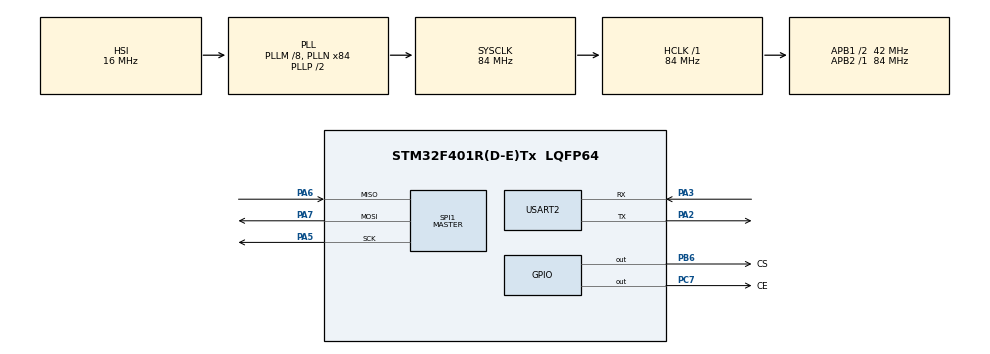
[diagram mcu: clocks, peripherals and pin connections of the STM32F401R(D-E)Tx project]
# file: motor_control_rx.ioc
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Mcu.Family=STM32F4
Mcu.Name=STM32F401R(D-E)Tx
Mcu.Package=LQFP64
NVIC.PriorityGroup=NVIC_PRIORITYGROUP_4
PA2.Mode=Asynchronous
PA2.Signal=USART2_TX
PA3.Mode=Asynchronous
PA3.Signal=USART2_RX
PA5.Mode=Full_Duplex_Master
PA5.Signal=SPI1_SCK
PA6.Mode=Full_Duplex_Master
PA6.Signal=SPI1_MISO
PA7.Mode=Full_Duplex_Master
PA7.Signal=SPI1_MOSI
PB6.GPIO_Label=CS
PB6.PinState=GPIO_PIN_SET
PB6.Signal=GPIO_Output
PC7.GPIO_Label=CE
PC7.Signal=GPIO_Output
ProjectManager.HeapSize=0x200
ProjectManager.StackSize=0x400
ProjectManager.TargetToolchain=STM32CubeIDE
RCC.48MHZClocksFreq_Value=42000000
RCC.AHBFreq_Value=84000000
RCC.APB1CLKDivider=RCC_HCLK_DIV2
RCC.APB1Freq_Value=42000000
RCC.APB1TimFreq_Value=84000000
RCC.APB2Freq_Value=84000000
RCC.APB2TimFreq_Value=84000000
RCC.CortexFreq_Value=84000000
RCC.HCLKFreq_Value=84000000
RCC.HSE_VALUE=25000000
RCC.HSI_VALUE=16000000
RCC.LSE_VALUE=32768
RCC.PLLM=8
RCC.PLLN=84
RCC.SYSCLKFreq_VALUE=84000000
RCC.SYSCLKSource=RCC_SYSCLKSOURCE_PLLCLK
RCC.VCOOutputFreq_Value=168000000
SPI1.BaudRatePrescaler=SPI_BAUDRATEPRESCALER_16
SPI1.Direction=SPI_DIRECTION_2LINES
SPI1.Mode=SPI_MODE_MASTER
SPI1.VirtualType=VM_MASTER
USART2.VirtualMode=VM_ASYNC
board=custom

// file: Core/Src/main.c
/* USER CODE BEGIN Header */
/**
  ******************************************************************************
  * @file           : main.c
  * @brief          : Main program body
  ******************************************************************************
  * @attention
  *
  * This program is setup to receive the joystick X and Y coordinates from the motor
  * control tx project. The coordinates will determine which direction(forward or reverse)
  * to set the motors in.
  *
  * Copyright (c) 2025 STMicroelectronics.
  * All rights reserved.
  *
  * This software is licensed under terms that can be found in the LICENSE file
  * in the root directory of this software component.
  * If no LICENSE file comes with this software, it is provided AS-IS.
  *
  ******************************************************************************
  */
/* USER CODE END Header */
#include "main.h"

/* USER CODE BEGIN Includes */
#include "NRF24L01.h"
#include "string.h"
#include "stdio.h"
/* USER CODE END Includes */

SPI_HandleTypeDef hspi1;

UART_HandleTypeDef huart2;

void SystemClock_Config(void);
static void MX_GPIO_Init(void);
static void MX_SPI1_Init(void);
static void MX_USART2_UART_Init(void);

/* USER CODE BEGIN 0 */

#define JOYSTICK_IN1_PORT GPIOA
#define JOYSTICK_IN1_PIN  GPIO_PIN_9
#define JOYSTICK_IN2_PORT GPIOA
#define JOYSTICK_IN2_PIN  GPIO_PIN_8
#define JOYSTICK_IN3_PORT GPIOB
#define JOYSTICK_IN3_PIN  GPIO_PIN_5
#define JOYSTICK_IN4_PORT GPIOB
#define JOYSTICK_IN4_PIN  GPIO_PIN_3

uint8_t rx_addr[] = {0xEE, 0xDD, 0xCC, 0xBB, 0xAA};
uint8_t rx_data[32];
char coordinate_arr[100];
uint8_t x_coordinate_val = 0;
uint8_t y_coordinate_val = 0;
uint8_t xy_coordinate_val[2];

// This function receives the x and y coordinates from the NRF24L01 rx module
// and assigns it to a  variable. This variable is later used to set the direction
// in the direction function
void joystick_coordiantes_rx()
{
		  if (data_available(1)==1)
		  {
			  rx(rx_data);

			  //rx buffer has the x data on the 0th element and y data on the 4th element due to a
			  //conversion from uint32_t to uint8_t in the motor_control tx project
			  xy_coordinate_val[0] = rx_data[0];
			  xy_coordinate_val[1] = rx_data[4];

			  //Used to debug and verify the correct coordinates are being transmitted to the NRF24L01 Receiver
			  sprintf(coordinate_arr,  "\rX-Coordinate: %d Y-Coordinate: %d \n", xy_coordinate_val[0],xy_coordinate_val[1]);
			  HAL_UART_Transmit(&huart2, (uint8_t*)coordinate_arr, 50, 1000);
		  }
}

//This function will execute a specific direction function for the motors
//based on the updated x and y coordinate values
void direction()
{

	while(1){

		joystick_coordiantes_rx();

		x_coordinate_val = xy_coordinate_val[0];
		y_coordinate_val = xy_coordinate_val[1];

		if (y_coordinate_val < 100)
		{
			forward(y_coordinate_val);
		}
		else if (y_coordinate_val > 160)
		{
			reverse(y_coordinate_val);
		}
		else if (x_coordinate_val >160)
		{
			clockwise(x_coordinate_val);
		}

		else if (x_coordinate_val <100)
		{
			counter_clockwise(x_coordinate_val);
		}

		else
		{
			no_move();
		}
	}

}

//This function sets both motors in the forward direction
void forward(y_coordinate_val)
{
	//check if were still moving in the same direction
	while(y_coordinate_val < 100)
	{
		HAL_GPIO_WritePin (JOYSTICK_IN1_PORT, JOYSTICK_IN1_PIN, 1);
		HAL_GPIO_WritePin (JOYSTICK_IN2_PORT, JOYSTICK_IN2_PIN, 0);
		HAL_GPIO_WritePin (JOYSTICK_IN3_PORT, JOYSTICK_IN3_PIN, 1);
		HAL_GPIO_WritePin (JOYSTICK_IN4_PORT, JOYSTICK_IN4_PIN, 0);

		//assigns xy_coordinate_val array to a new set of x and y coordinates from the RF module
		joystick_coordiantes_rx();

		//update y variable to use the most updated joystick value
		y_coordinate_val = xy_coordinate_val[1];
	}
}

//This function sets both motors in the reverse direction
void reverse(y_coordinate_val)
{
	//check if were still moving in the same direction
	while(y_coordinate_val > 160)
	{
		HAL_GPIO_WritePin (JOYSTICK_IN1_PORT, JOYSTICK_IN1_PIN, 0);
		HAL_GPIO_WritePin (JOYSTICK_IN2_PORT, JOYSTICK_IN2_PIN, 1);
		HAL_GPIO_WritePin (JOYSTICK_IN3_PORT, JOYSTICK_IN3_PIN, 0);
		HAL_GPIO_WritePin (JOYSTICK_IN4_PORT, JOYSTICK_IN4_PIN, 1);

		//assigns xy_coordinate_val array to a new set of x and y coordinates from the RF module
		joystick_coordiantes_rx();

		//update y variable to use the most updated joystick value
		y_coordinate_val = xy_coordinate_val[1];
	}
}

//This function sets the left motor in the forward direction and turns the right motor off
void clockwise(x_coordinate_val)
{
	//check if were still moving in the same direction
	while(x_coordinate_val > 160)
	{
		HAL_GPIO_WritePin (JOYSTICK_IN1_PORT, JOYSTICK_IN1_PIN, 1);
		HAL_GPIO_WritePin (JOYSTICK_IN2_PORT, JOYSTICK_IN2_PIN, 0);
		HAL_GPIO_WritePin (JOYSTICK_IN3_PORT, JOYSTICK_IN3_PIN, 0);
		HAL_GPIO_WritePin (JOYSTICK_IN4_PORT, JOYSTICK_IN4_PIN, 0);

		//assigns xy_coordinate_val array to a new set of x and y coordinates from the RF module
		joystick_coordiantes_rx();

		//update y variable to use the most updated joystick value
		x_coordinate_val = xy_coordinate_val[0];
	}
}

//This function sets the right motor in the forward direction and turns the left motor off
void counter_clockwise(x_coordinate_val)
{
	//check if were still moving in the same direction
	while(x_coordinate_val < 100)
	{
		HAL_GPIO_WritePin (JOYSTICK_IN1_PORT, JOYSTICK_IN1_PIN, 0);
		HAL_GPIO_WritePin (JOYSTICK_IN2_PORT, JOYSTICK_IN2_PIN, 0);
		HAL_GPIO_WritePin (JOYSTICK_IN3_PORT, JOYSTICK_IN3_PIN, 1);
		HAL_GPIO_WritePin (JOYSTICK_IN4_PORT, JOYSTICK_IN4_PIN, 0);

		//assigns xy_coordinate_val array to a new set of x and y coordinates from the RF module
		joystick_coordiantes_rx();

		//update y variable to use the most updated joystick value
		x_coordinate_val = xy_coordinate_val[0];
	}
}

//turn both motors off
void no_move()
{
		HAL_GPIO_WritePin (JOYSTICK_IN1_PORT, JOYSTICK_IN1_PIN, 0);
		HAL_GPIO_WritePin (JOYSTICK_IN2_PORT, JOYSTICK_IN2_PIN, 0);
		HAL_GPIO_WritePin (JOYSTICK_IN3_PORT, JOYSTICK_IN3_PIN, 0);
		HAL_GPIO_WritePin (JOYSTICK_IN4_PORT, JOYSTICK_IN4_PIN, 0);
}

/* USER CODE END 0 */

int main(void)
{

  /* USER CODE BEGIN 1 */
//	uint8_t xy_coordinate_val[2];

  /* USER CODE END 1 */

  /* MCU Configuration--------------------------------------------------------*/

  /* Reset of all peripherals, Initializes the Flash interface and the Systick. */
  HAL_Init();

  /* Configure the system clock */
  SystemClock_Config();

  /* Initialize all configured peripherals */
  MX_GPIO_Init();
  MX_SPI1_Init();
  MX_USART2_UART_Init();
  /* USER CODE BEGIN 2 */
  nrf24_init();
  setup_rx_mode(rx_addr, 100);
  HAL_Delay (1000);

  /* USER CODE END 2 */

  /* Infinite loop */
  while (1)
  {

    /* USER CODE BEGIN 3 */
	  direction();
  }
  /* USER CODE END 3 */
}

void SystemClock_Config(void)
{
  RCC_OscInitTypeDef RCC_OscInitStruct = {0};
  RCC_ClkInitTypeDef RCC_ClkInitStruct = {0};

  /** Configure the main internal regulator output voltage
  */
  __HAL_RCC_PWR_CLK_ENABLE();
  __HAL_PWR_VOLTAGESCALING_CONFIG(PWR_REGULATOR_VOLTAGE_SCALE2);

  /** Initializes the RCC Oscillators according to the specified parameters
  * in the RCC_OscInitTypeDef structure.
  */
  RCC_OscInitStruct.OscillatorType = RCC_OSCILLATORTYPE_HSI;
  RCC_OscInitStruct.HSIState = RCC_HSI_ON;
  RCC_OscInitStruct.HSICalibrationValue = RCC_HSICALIBRATION_DEFAULT;
  RCC_OscInitStruct.PLL.PLLState = RCC_PLL_ON;
  RCC_OscInitStruct.PLL.PLLSource = RCC_PLLSOURCE_HSI;
  RCC_OscInitStruct.PLL.PLLM = 8;
  RCC_OscInitStruct.PLL.PLLN = 84;
  RCC_OscInitStruct.PLL.PLLP = RCC_PLLP_DIV2;
  RCC_OscInitStruct.PLL.PLLQ = 4;
  if (HAL_RCC_OscConfig(&RCC_OscInitStruct) != HAL_OK)
  {
    Error_Handler();
  }

  /** Initializes the CPU, AHB and APB buses clocks
  */
  RCC_ClkInitStruct.ClockType = RCC_CLOCKTYPE_HCLK|RCC_CLOCKTYPE_SYSCLK
                              |RCC_CLOCKTYPE_PCLK1|RCC_CLOCKTYPE_PCLK2;
  RCC_ClkInitStruct.SYSCLKSource = RCC_SYSCLKSOURCE_PLLCLK;
  RCC_ClkInitStruct.AHBCLKDivider = RCC_SYSCLK_DIV1;
  RCC_ClkInitStruct.APB1CLKDivider = RCC_HCLK_DIV2;
  RCC_ClkInitStruct.APB2CLKDivider = RCC_HCLK_DIV1;

  if (HAL_RCC_ClockConfig(&RCC_ClkInitStruct, FLASH_LATENCY_2) != HAL_OK)
  {
    Error_Handler();
  }
}

static void MX_SPI1_Init(void)
{

  /* SPI1 parameter configuration*/
  hspi1.Instance = SPI1;
  hspi1.Init.Mode = SPI_MODE_MASTER;
  hspi1.Init.Direction = SPI_DIRECTION_2LINES;
  hspi1.Init.DataSize = SPI_DATASIZE_8BIT;
  hspi1.Init.CLKPolarity = SPI_POLARITY_LOW;
  hspi1.Init.CLKPhase = SPI_PHASE_1EDGE;
  hspi1.Init.NSS = SPI_NSS_SOFT;
  hspi1.Init.BaudRatePrescaler = SPI_BAUDRATEPRESCALER_16;
  hspi1.Init.FirstBit = SPI_FIRSTBIT_MSB;
  hspi1.Init.TIMode = SPI_TIMODE_DISABLE;
  hspi1.Init.CRCCalculation = SPI_CRCCALCULATION_DISABLE;
  hspi1.Init.CRCPolynomial = 10;
  if (HAL_SPI_Init(&hspi1) != HAL_OK)
  {
    Error_Handler();
  }

}

static void MX_USART2_UART_Init(void)
{

  huart2.Instance = USART2;
  huart2.Init.BaudRate = 115200;
  huart2.Init.WordLength = UART_WORDLENGTH_8B;
  huart2.Init.StopBits = UART_STOPBITS_1;
  huart2.Init.Parity = UART_PARITY_NONE;
  huart2.Init.Mode = UART_MODE_TX_RX;
  huart2.Init.HwFlowCtl = UART_HWCONTROL_NONE;
  huart2.Init.OverSampling = UART_OVERSAMPLING_16;
  if (HAL_UART_Init(&huart2) != HAL_OK)
  {
    Error_Handler();
  }

}

static void MX_GPIO_Init(void)
{
  GPIO_InitTypeDef GPIO_InitStruct = {0};

  /* GPIO Ports Clock Enable */
  __HAL_RCC_GPIOA_CLK_ENABLE();
  __HAL_RCC_GPIOC_CLK_ENABLE();
  __HAL_RCC_GPIOB_CLK_ENABLE();

  /*Configure GPIO pin Output Level */
  HAL_GPIO_WritePin(CE_GPIO_Port, CE_Pin, GPIO_PIN_RESET);

  /*Configure GPIO pin Output Level */
  HAL_GPIO_WritePin(GPIOA, IN2_Pin|IN1_Pin, GPIO_PIN_RESET);

  /*Configure GPIO pin Output Level */
  HAL_GPIO_WritePin(GPIOB, IN4_Pin|IN3_Pin, GPIO_PIN_RESET);

  /*Configure GPIO pin Output Level */
  HAL_GPIO_WritePin(CS_GPIO_Port, CS_Pin, GPIO_PIN_SET);

  /*Configure GPIO pin : CE_Pin */
  GPIO_InitStruct.Pin = CE_Pin;
  GPIO_InitStruct.Mode = GPIO_MODE_OUTPUT_PP;
  GPIO_InitStruct.Pull = GPIO_NOPULL;
  GPIO_InitStruct.Speed = GPIO_SPEED_FREQ_LOW;
  HAL_GPIO_Init(CE_GPIO_Port, &GPIO_InitStruct);

  /*Configure GPIO pins : IN2_Pin IN1_Pin */
  GPIO_InitStruct.Pin = IN2_Pin|IN1_Pin;
  GPIO_InitStruct.Mode = GPIO_MODE_OUTPUT_PP;
  GPIO_InitStruct.Pull = GPIO_NOPULL;
  GPIO_InitStruct.Speed = GPIO_SPEED_FREQ_LOW;
  HAL_GPIO_Init(GPIOA, &GPIO_InitStruct);

  /*Configure GPIO pins : IN4_Pin IN3_Pin CS_Pin */
  GPIO_InitStruct.Pin = IN4_Pin|IN3_Pin|CS_Pin;
  GPIO_InitStruct.Mode = GPIO_MODE_OUTPUT_PP;
  GPIO_InitStruct.Pull = GPIO_NOPULL;
  GPIO_InitStruct.Speed = GPIO_SPEED_FREQ_LOW;
  HAL_GPIO_Init(GPIOB, &GPIO_InitStruct);

}

void Error_Handler(void)
{
  __disable_irq();
  while (1)
  {
  }
}
